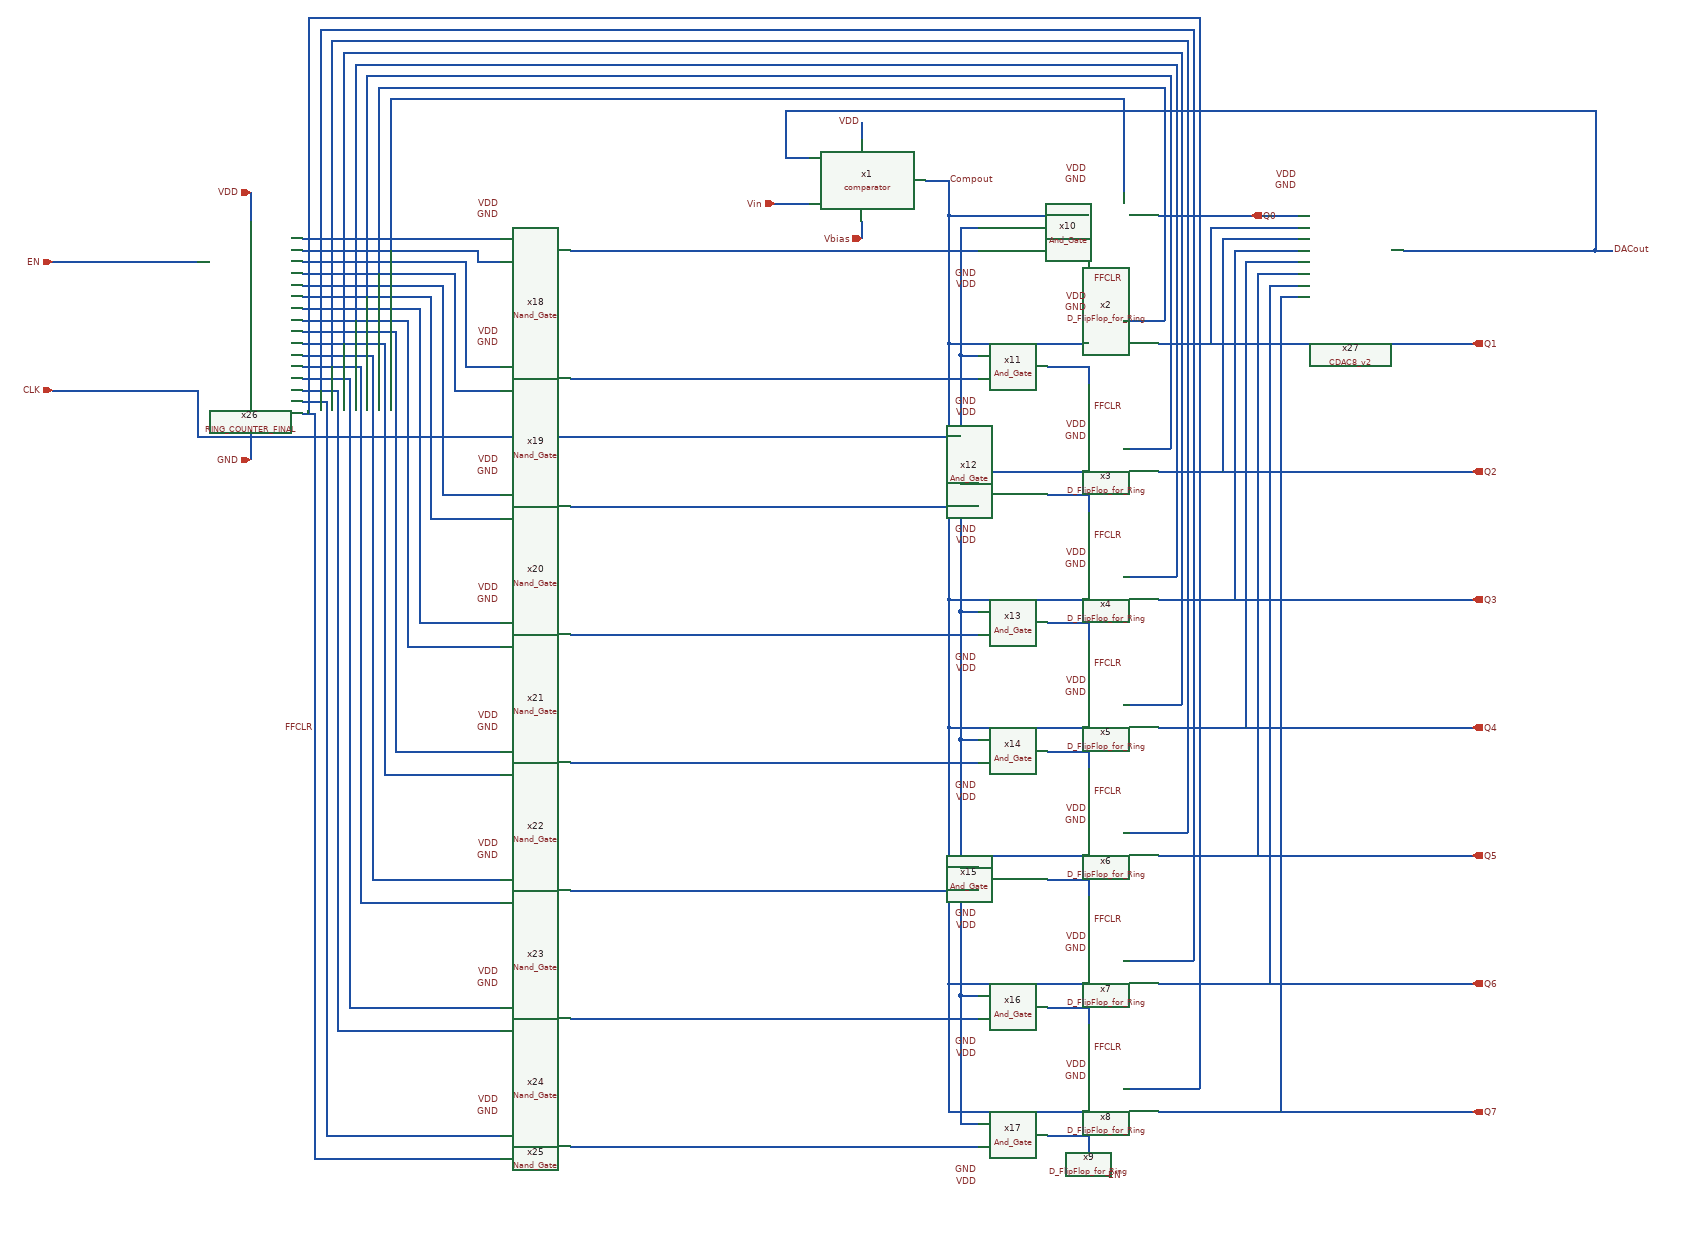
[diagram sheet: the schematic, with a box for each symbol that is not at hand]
v {xschem version=3.4.5 file_version=1.2
}
G {}
K {}
V {}
S {}
E {}
N 2860 1340 3020 1340 {
lab=Q7}
N 2860 1120 3000 1120 {
lab=Q6}
N 2860 900 2980 900 {
lab=Q5}
N 2420 -260 2460 -260 {
lab=Compout}
N 2460 -260 2460 -200 {
lab=Compout}
N 2460 -200 2700 -200 {
lab=Compout}
N 2460 -200 2460 20 {
lab=Compout}
N 2460 20 2700 20 {
lab=Compout}
N 2460 20 2460 240 {
lab=Compout}
N 2460 240 2700 240 {
lab=Compout}
N 2460 240 2460 460 {
lab=Compout}
N 2460 460 2700 460 {
lab=Compout}
N 2460 460 2460 680 {
lab=Compout}
N 2460 680 2700 680 {
lab=Compout}
N 2460 900 2700 900 {
lab=Compout}
N 2460 680 2460 900 {
lab=Compout}
N 2460 1120 2700 1120 {
lab=Compout}
N 2460 900 2460 1120 {
lab=Compout}
N 2460 1340 2700 1340 {
lab=Compout}
N 2460 1120 2460 1340 {
lab=Compout}
N 2480 -180 2480 40 {
lab=CLK}
N 2480 480 2480 700 {
lab=CLK}
N 2480 700 2480 1140 {
lab=CLK}
N 2480 1140 2480 1360 {
lab=CLK}
N 2180 -300 2220 -300 {
lab=DACout}
N 2180 -380 2180 -300 {
lab=DACout}
N 2180 -380 3280 -380 {
lab=DACout}
N 2700 -160 2700 -130 {
lab=#net1}
N 2700 280 2700 310 {
lab=#net2}
N 2700 500 2700 530 {
lab=#net3}
N 2700 720 2700 750 {
lab=#net4}
N 2820 680 2860 680 {
lab=Q4}
N 2700 940 2700 970 {
lab=#net5}
N 2820 900 2860 900 {
lab=Q5}
N 2700 1160 2700 1190 {
lab=#net6}
N 2820 1120 2860 1120 {
lab=Q6}
N 2820 1340 2860 1340 {
lab=Q7}
N 2700 1380 2700 1410 {
lab=#net7}
N 2700 60 2700 90 {
lab=#net8}
N 2820 20 2900 20 {
lab=Q1}
N 960 -120 1170 -120 {
lab=EN}
N 960 100 1170 100 {
lab=CLK}
N 2160 -220 2220 -220 {
lab=Vin}
N 920 -120 960 -120 {
lab=EN}
N 920 100 960 100 {
lab=CLK}
N 2900 20 3360 20 {
lab=Q1}
N 2980 900 3360 900 {
lab=Q5}
N 3000 1120 3360 1120 {
lab=Q6}
N 3020 1340 3360 1340 {
lab=Q7}
N 1170 100 1170 180 {
lab=CLK}
N 1170 180 2480 180 {
lab=CLK}
N 2820 240 3360 240 {
lab=Q2}
N 2860 680 3360 680 {
lab=Q4}
N 2820 460 3360 460 {
lab=Q3}
N 3280 -380 3570 -380 {
lab=DACout}
N 3570 -380 3570 -140 {
lab=DACout}
N 3030 -60 3030 1340 {
lab=Q7}
N 3010 -80 3010 1120 {
lab=Q6}
N 2990 -100 2990 900 {
lab=Q5}
N 2970 -120 2970 680 {
lab=Q4}
N 2950 -140 2950 460 {
lab=Q3}
N 2930 -160 2930 240 {
lab=Q2}
N 2910 -180 2910 20 {
lab=Q1}
N 1350 140 1370 140 {
lab=FFCLR}
N 1370 140 1370 1420 {
lab=FFCLR}
N 1370 1420 1690 1420 {
lab=FFCLR}
N 1350 -160 1690 -160 {
lab=#net9}
N 1390 1380 1690 1380 {
lab=#net10}
N 1390 120 1390 1380 {
lab=#net10}
N 1350 120 1390 120 {
lab=#net10}
N 1350 100 1410 100 {
lab=#net11}
N 1410 100 1410 1200 {
lab=#net11}
N 1410 1200 1690 1200 {
lab=#net11}
N 1430 1160 1690 1160 {
lab=#net12}
N 1430 80 1430 1160 {
lab=#net12}
N 1350 80 1430 80 {
lab=#net12}
N 1350 60 1450 60 {
lab=#net13}
N 1450 60 1450 980 {
lab=#net13}
N 1450 980 1690 980 {
lab=#net13}
N 1470 940 1690 940 {
lab=#net14}
N 1470 40 1470 940 {
lab=#net14}
N 1350 40 1470 40 {
lab=#net14}
N 1350 20 1490 20 {
lab=#net15}
N 1490 20 1490 760 {
lab=#net15}
N 1490 760 1690 760 {
lab=#net15}
N 1510 720 1690 720 {
lab=#net16}
N 1510 0 1510 720 {
lab=#net16}
N 1350 0 1510 0 {
lab=#net16}
N 1350 -20 1530 -20 {
lab=#net17}
N 1350 -40 1550 -40 {
lab=#net18}
N 1350 -60 1570 -60 {
lab=#net19}
N 1350 -80 1590 -80 {
lab=#net20}
N 1350 -100 1610 -100 {
lab=#net21}
N 1350 -120 1630 -120 {
lab=#net22}
N 1350 -140 1650 -140 {
lab=#net23}
N 1650 -140 1650 -120 {
lab=#net23}
N 1650 -120 1690 -120 {
lab=#net23}
N 1630 -120 1630 60 {
lab=#net22}
N 1630 60 1690 60 {
lab=#net22}
N 1610 -100 1610 100 {
lab=#net21}
N 1610 100 1690 100 {
lab=#net21}
N 1590 -80 1590 280 {
lab=#net20}
N 1590 280 1690 280 {
lab=#net20}
N 1570 320 1690 320 {
lab=#net19}
N 1570 -60 1570 320 {
lab=#net19}
N 1550 -40 1550 500 {
lab=#net18}
N 1550 500 1690 500 {
lab=#net18}
N 1530 540 1690 540 {
lab=#net17}
N 1530 -20 1530 540 {
lab=#net17}
N 2760 -400 2760 -240 {
lab=#net23}
N 1610 -400 2760 -400 {
lab=#net23}
N 1500 -400 1500 -140 {
lab=#net23}
N 1480 -420 1480 -100 {
lab=#net21}
N 2830 -420 2830 -20 {
lab=#net21}
N 2840 -440 2840 200 {
lab=#net19}
N 2850 -460 2850 420 {
lab=#net17}
N 2860 -480 2860 640 {
lab=#net15}
N 2870 -500 2870 860 {
lab=#net13}
N 2880 -520 2880 1080 {
lab=#net11}
N 1590 -420 2830 -420 {
lab=#net21}
N 2760 -20 2830 -20 {
lab=#net21}
N 2760 200 2840 200 {
lab=#net19}
N 2760 420 2850 420 {
lab=#net17}
N 2760 640 2860 640 {
lab=#net15}
N 2760 860 2870 860 {
lab=#net13}
N 2760 1080 2880 1080 {
lab=#net11}
N 2890 -540 2890 1300 {
lab=FFCLR}
N 2760 1300 2890 1300 {
lab=FFCLR}
N 1570 -440 2840 -440 {
lab=#net19}
N 1460 -440 1460 -60 {
lab=#net19}
N 1550 -460 2850 -460 {
lab=#net17}
N 1570 -400 1610 -400 {
lab=#net23}
N 1550 -420 1590 -420 {
lab=#net21}
N 1530 -440 1570 -440 {
lab=#net19}
N 1510 -460 1550 -460 {
lab=#net17}
N 1440 -460 1440 -20 {
lab=#net17}
N 1420 -480 1420 20 {
lab=#net15}
N 1490 -480 2860 -480 {
lab=#net15}
N 1400 -490 1400 60 {
lab=#net13}
N 1380 -520 1380 100 {
lab=#net11}
N 1360 -540 1360 140 {
lab=FFCLR}
N 1360 -540 2890 -540 {
lab=FFCLR}
N 1380 -520 2880 -520 {
lab=#net11}
N 1500 -400 1570 -400 {
lab=#net23}
N 1480 -420 1550 -420 {
lab=#net21}
N 1460 -440 1530 -440 {
lab=#net19}
N 1440 -460 1510 -460 {
lab=#net17}
N 1420 -480 1490 -480 {
lab=#net15}
N 1400 -500 1400 -490 {
lab=#net13}
N 1400 -500 2870 -500 {
lab=#net13}
N 3570 -140 3600 -140 {
lab=DACout}
N 2820 -200 2910 -200 {
lab=Q0}
N 2970 -200 3060 -200 {
lab=Q0}
N 2910 -180 2990 -180 {
lab=Q1}
N 3050 -180 3060 -180 {
lab=Q1}
N 2930 -160 2990 -160 {
lab=Q2}
N 3050 -160 3060 -160 {
lab=Q2}
N 2950 -140 2990 -140 {
lab=Q3}
N 3050 -140 3060 -140 {
lab=Q3}
N 3050 -100 3060 -100 {
lab=Q5}
N 3030 -60 3060 -60 {
lab=Q7}
N 3010 -80 3060 -80 {
lab=Q6}
N 2990 -180 3050 -180 {
lab=Q1}
N 2990 -160 3050 -160 {
lab=Q2}
N 2990 -140 3050 -140 {
lab=Q3}
N 2990 -100 3050 -100 {
lab=Q5}
N 3240 -140 3570 -140 {
lab=DACout}
N 2970 -120 3060 -120 {
lab=Q4}
N 2310 -360 2310 -330 {
lab=VDD}
N 2310 -190 2310 -160 {
lab=Vbias}
N 2480 40 2480 270 {
lab=CLK}
N 1810 1400 2510 1400 {
lab=#net24}
N 1810 300 2510 300 {
lab=#net25}
N 1810 520 2510 520 {
lab=#net26}
N 1810 740 2510 740 {
lab=#net27}
N 1810 960 2510 960 {
lab=#net28}
N 1810 1180 2510 1180 {
lab=#net29}
N 1810 -140 2510 -140 {
lab=#net30}
N 1810 80 2510 80 {
lab=#net31}
N 2630 -160 2700 -160 {
lab=#net1}
N 2630 60 2700 60 {
lab=#net8}
N 2630 280 2700 280 {
lab=#net2}
N 2630 500 2700 500 {
lab=#net3}
N 2630 720 2700 720 {
lab=#net4}
N 2630 940 2700 940 {
lab=#net5}
N 2630 1160 2700 1160 {
lab=#net6}
N 2630 1380 2700 1380 {
lab=#net7}
N 2480 1140 2510 1140 {
lab=CLK}
N 2480 1360 2510 1360 {
lab=CLK}
N 2480 700 2510 700 {
lab=CLK}
N 2480 920 2510 920 {
lab=CLK}
N 2480 270 2480 480 {
lab=CLK}
N 2480 480 2510 480 {
lab=CLK}
N 2480 260 2510 260 {
lab=CLK}
N 2480 40 2510 40 {
lab=CLK}
N 2480 -180 2510 -180 {
lab=CLK}
N 1260 170 1260 220 {
lab=GND}
N 1260 -240 1260 -190 {
lab=VDD}
N 2910 -200 2970 -200 {
lab=Q0}
C {D_FlipFlop_for_Ring.sym} 2800 -40 0 0 {name=x2}
C {D_FlipFlop_for_Ring.sym} 2800 400 0 0 {name=x4}
C {D_FlipFlop_for_Ring.sym} 2800 620 0 0 {name=x5}
C {D_FlipFlop_for_Ring.sym} 2800 840 0 0 {name=x6}
C {D_FlipFlop_for_Ring.sym} 2800 1060 0 0 {name=x7}
C {D_FlipFlop_for_Ring.sym} 2800 1280 0 0 {name=x8}
C {D_FlipFlop_for_Ring.sym} 2800 1500 0 0 {name=x9}
C {D_FlipFlop_for_Ring.sym} 2800 180 0 0 {name=x3}
C {devices/ipin.sym} 920 -120 0 0 {name=p4 sig_type=std_logic lab=EN}
C {devices/ipin.sym} 920 100 0 0 {name=p1 sig_type=std_logic lab=CLK}
C {devices/ipin.sym} 1260 -240 0 0 {name=p2 sig_type=std_logic lab=VDD}
C {devices/ipin.sym} 2160 -220 0 0 {name=p3 sig_type=std_logic lab=Vin}
C {devices/opin.sym} 2980 -200 3 0 {name=p11 lab=Q0}
C {devices/opin.sym} 3360 240 0 0 {name=p6 lab=Q2}
C {devices/opin.sym} 3360 460 0 0 {name=p7 lab=Q3}
C {devices/opin.sym} 3360 680 0 0 {name=p8 lab=Q4}
C {devices/opin.sym} 3360 900 0 0 {name=p9 lab=Q5}
C {devices/opin.sym} 3360 1120 0 0 {name=p10 lab=Q6}
C {devices/opin.sym} 3360 1340 0 0 {name=p12 lab=Q7}
C {Nand_Gate.sym} 1750 -30 0 0 {name=x18}
C {Nand_Gate.sym} 1750 190 0 0 {name=x19}
C {Nand_Gate.sym} 1750 410 0 0 {name=x20}
C {Nand_Gate.sym} 1750 630 0 0 {name=x21}
C {And_Gate.sym} 2590 -240 2 1 {name=x10}
C {CDAC8_v2.sym} 2980 -20 0 0 {name=x27}
C {comparator.sym} 2360 -260 0 0 {name=x1}
C {RING_COUNTER_FINAL.sym} 1260 -70 0 0 {name=x26}
C {devices/opin.sym} 3360 20 0 0 {name=p30 lab=Q1}
C {devices/lab_wire.sym} 1370 680 0 0 {name=p5 sig_type=std_logic lab=FFCLR}
C {devices/lab_wire.sym} 2760 1230 0 0 {name=p19 sig_type=std_logic lab=FFCLR}
C {devices/lab_wire.sym} 2760 1010 0 0 {name=p18 sig_type=std_logic lab=FFCLR}
C {devices/lab_wire.sym} 2760 790 0 0 {name=p17 sig_type=std_logic lab=FFCLR}
C {devices/lab_wire.sym} 2760 570 0 0 {name=p16 sig_type=std_logic lab=FFCLR}
C {devices/lab_wire.sym} 2760 350 0 0 {name=p15 sig_type=std_logic lab=FFCLR}
C {devices/lab_wire.sym} 2760 130 0 0 {name=p14 sig_type=std_logic lab=FFCLR}
C {devices/lab_wire.sym} 2760 -90 0 0 {name=p13 sig_type=std_logic lab=FFCLR}
C {devices/ipin.sym} 2310 -160 0 0 {name=p33 sig_type=std_logic lab=Vbias}
C {devices/lab_wire.sym} 3600 -140 0 1 {name=p27 sig_type=std_logic lab=DACout}
C {devices/lab_wire.sym} 2460 -260 0 1 {name=p22 sig_type=std_logic lab=Compout}
C {devices/lab_wire.sym} 2310 -360 0 0 {name=p23 sig_type=std_logic lab=VDD}
C {devices/lab_wire.sym} 2760 1450 2 1 {name=p21 sig_type=std_logic lab=EN}
C {devices/ipin.sym} 1260 220 0 0 {name=p31 sig_type=std_logic lab=GND}
C {devices/lab_wire.sym} 1690 -220 0 0 {name=p32 sig_type=std_logic lab=VDD}
C {devices/lab_wire.sym} 1690 -200 0 0 {name=p34 sig_type=std_logic lab=GND}
C {devices/lab_wire.sym} 1690 0 0 0 {name=p35 sig_type=std_logic lab=VDD}
C {devices/lab_wire.sym} 1690 20 0 0 {name=p36 sig_type=std_logic lab=GND}
C {devices/lab_wire.sym} 1690 220 0 0 {name=p37 sig_type=std_logic lab=VDD}
C {devices/lab_wire.sym} 1690 240 0 0 {name=p38 sig_type=std_logic lab=GND}
C {devices/lab_wire.sym} 1690 440 0 0 {name=p39 sig_type=std_logic lab=VDD}
C {devices/lab_wire.sym} 1690 460 0 0 {name=p40 sig_type=std_logic lab=GND}
C {devices/lab_wire.sym} 2700 1260 0 0 {name=p53 sig_type=std_logic lab=VDD}
C {devices/lab_wire.sym} 2700 1280 0 0 {name=p54 sig_type=std_logic lab=GND}
C {devices/lab_wire.sym} 2700 1040 0 0 {name=p55 sig_type=std_logic lab=VDD}
C {devices/lab_wire.sym} 2700 1060 0 0 {name=p56 sig_type=std_logic lab=GND}
C {devices/lab_wire.sym} 2700 820 0 0 {name=p57 sig_type=std_logic lab=VDD}
C {devices/lab_wire.sym} 2700 840 0 0 {name=p58 sig_type=std_logic lab=GND}
C {devices/lab_wire.sym} 2700 600 0 0 {name=p61 sig_type=std_logic lab=VDD}
C {devices/lab_wire.sym} 2700 620 0 0 {name=p62 sig_type=std_logic lab=GND}
C {devices/lab_wire.sym} 2700 380 0 0 {name=p65 sig_type=std_logic lab=VDD}
C {devices/lab_wire.sym} 2700 400 0 0 {name=p66 sig_type=std_logic lab=GND}
C {devices/lab_wire.sym} 2510 -80 0 0 {name=p73 sig_type=std_logic lab=VDD}
C {devices/lab_wire.sym} 2510 -100 0 0 {name=p74 sig_type=std_logic lab=GND}
C {devices/lab_wire.sym} 2700 -280 0 0 {name=p75 sig_type=std_logic lab=VDD}
C {devices/lab_wire.sym} 2700 -260 0 0 {name=p76 sig_type=std_logic lab=GND}
C {devices/lab_wire.sym} 3060 -270 0 0 {name=p20 sig_type=std_logic lab=VDD}
C {devices/lab_wire.sym} 3060 -250 0 0 {name=p24 sig_type=std_logic lab=GND}
C {devices/lab_wire.sym} 2700 -60 0 0 {name=p25 sig_type=std_logic lab=VDD}
C {devices/lab_wire.sym} 2700 -40 0 0 {name=p26 sig_type=std_logic lab=GND}
C {devices/lab_wire.sym} 2700 160 0 0 {name=p28 sig_type=std_logic lab=VDD}
C {devices/lab_wire.sym} 2700 180 0 0 {name=p29 sig_type=std_logic lab=GND}
C {devices/noconn.sym} 2820 -130 2 0 {name=l2}
C {devices/noconn.sym} 2820 90 2 0 {name=l1}
C {devices/noconn.sym} 2820 310 2 0 {name=l3}
C {devices/noconn.sym} 2820 530 2 0 {name=l4}
C {devices/noconn.sym} 2820 970 2 0 {name=l5}
C {devices/noconn.sym} 2820 750 2 0 {name=l6}
C {devices/noconn.sym} 2820 1190 2 0 {name=l7}
C {devices/noconn.sym} 2820 1410 2 0 {name=l8}
C {Nand_Gate.sym} 1750 850 0 0 {name=x22}
C {Nand_Gate.sym} 1750 1070 0 0 {name=x23}
C {Nand_Gate.sym} 1750 1290 0 0 {name=x24}
C {Nand_Gate.sym} 1750 1510 0 0 {name=x25}
C {devices/lab_wire.sym} 1690 660 0 0 {name=p41 sig_type=std_logic lab=VDD}
C {devices/lab_wire.sym} 1690 680 0 0 {name=p42 sig_type=std_logic lab=GND}
C {devices/lab_wire.sym} 1690 880 0 0 {name=p43 sig_type=std_logic lab=VDD}
C {devices/lab_wire.sym} 1690 900 0 0 {name=p44 sig_type=std_logic lab=GND}
C {devices/lab_wire.sym} 1690 1100 0 0 {name=p45 sig_type=std_logic lab=VDD}
C {devices/lab_wire.sym} 1690 1120 0 0 {name=p46 sig_type=std_logic lab=GND}
C {devices/lab_wire.sym} 1690 1320 0 0 {name=p47 sig_type=std_logic lab=VDD}
C {devices/lab_wire.sym} 1690 1340 0 0 {name=p48 sig_type=std_logic lab=GND}
C {And_Gate.sym} 2590 -20 2 1 {name=x11}
C {devices/lab_wire.sym} 2510 140 0 0 {name=p49 sig_type=std_logic lab=VDD}
C {devices/lab_wire.sym} 2510 120 0 0 {name=p50 sig_type=std_logic lab=GND}
C {And_Gate.sym} 2590 200 2 1 {name=x12}
C {devices/lab_wire.sym} 2510 360 0 0 {name=p59 sig_type=std_logic lab=VDD}
C {devices/lab_wire.sym} 2510 340 0 0 {name=p60 sig_type=std_logic lab=GND}
C {And_Gate.sym} 2590 420 2 1 {name=x13}
C {devices/lab_wire.sym} 2510 580 0 0 {name=p63 sig_type=std_logic lab=VDD}
C {devices/lab_wire.sym} 2510 560 0 0 {name=p64 sig_type=std_logic lab=GND}
C {And_Gate.sym} 2590 640 2 1 {name=x14}
C {devices/lab_wire.sym} 2510 800 0 0 {name=p51 sig_type=std_logic lab=VDD}
C {devices/lab_wire.sym} 2510 780 0 0 {name=p52 sig_type=std_logic lab=GND}
C {And_Gate.sym} 2590 860 2 1 {name=x15}
C {devices/lab_wire.sym} 2510 1020 0 0 {name=p67 sig_type=std_logic lab=VDD}
C {devices/lab_wire.sym} 2510 1000 0 0 {name=p68 sig_type=std_logic lab=GND}
C {And_Gate.sym} 2590 1080 2 1 {name=x16}
C {devices/lab_wire.sym} 2510 1240 0 0 {name=p69 sig_type=std_logic lab=VDD}
C {devices/lab_wire.sym} 2510 1220 0 0 {name=p70 sig_type=std_logic lab=GND}
C {And_Gate.sym} 2590 1300 2 1 {name=x17}
C {devices/lab_wire.sym} 2510 1460 0 0 {name=p71 sig_type=std_logic lab=VDD}
C {devices/lab_wire.sym} 2510 1440 0 0 {name=p72 sig_type=std_logic lab=GND}
